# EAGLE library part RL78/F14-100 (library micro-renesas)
16-Bit Single-Chip Microcontroller Source: Data sheet

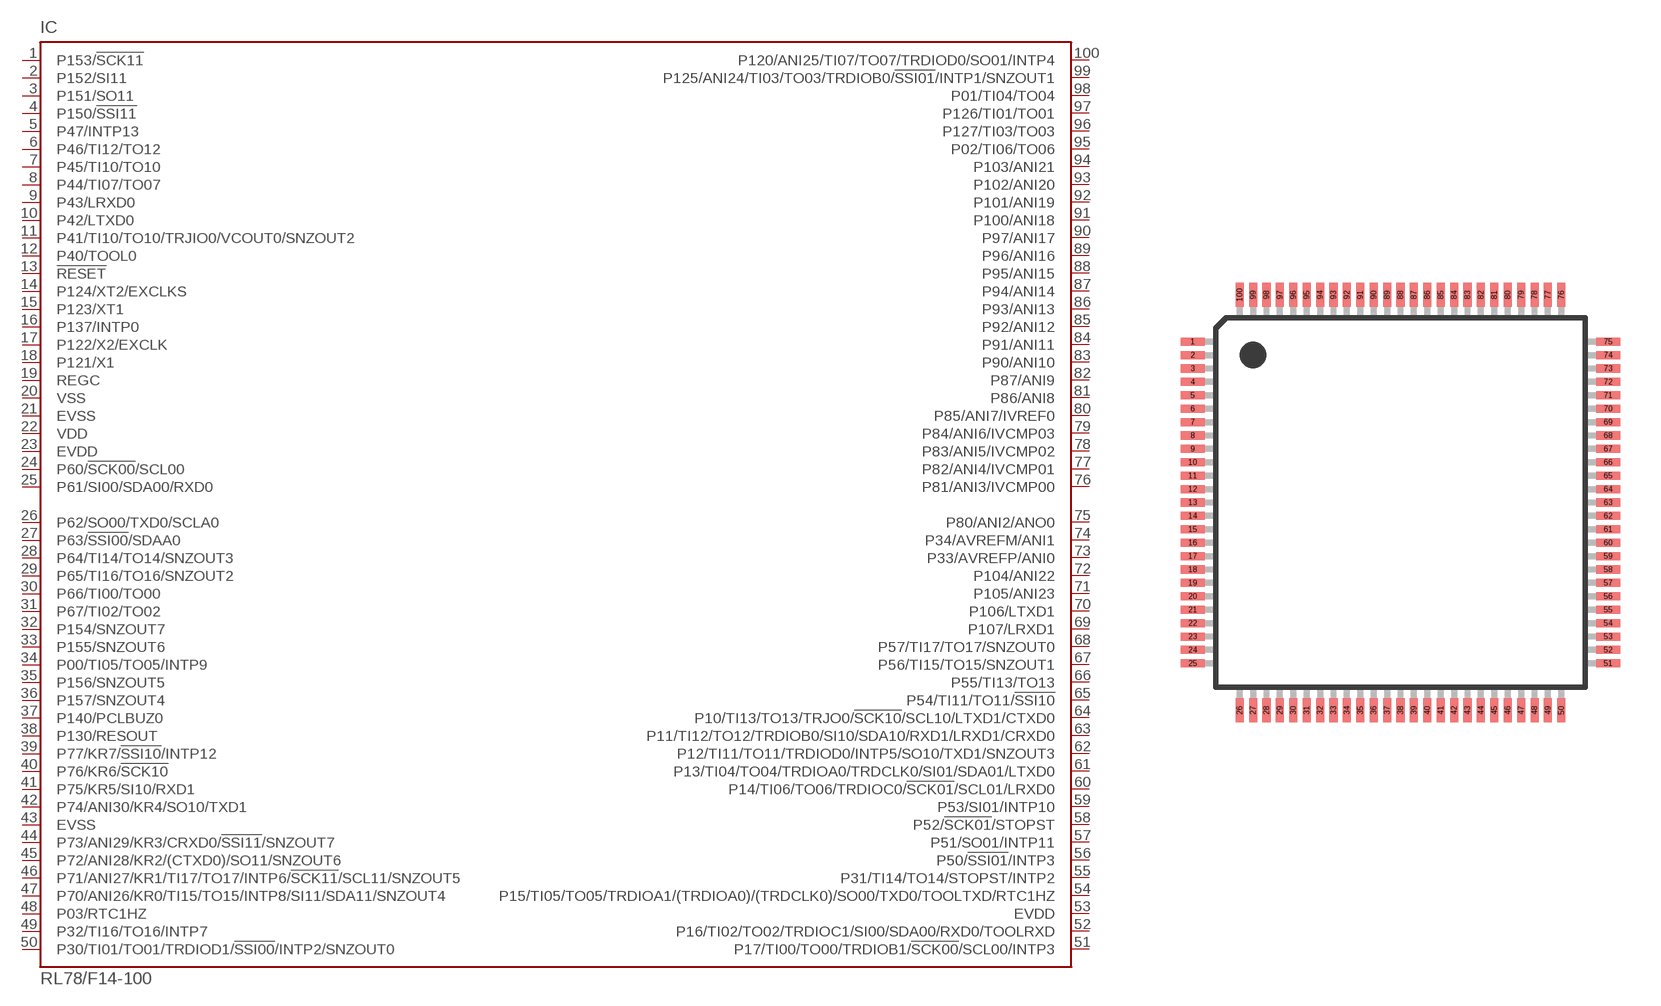
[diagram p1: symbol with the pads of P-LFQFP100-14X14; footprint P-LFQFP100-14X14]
Designator prefix IC

## RL78/F14-100  [P-LFQFP100-14X14]
1  P153/!SCK11
2  P152/SI11
3  P151/SO11
4  P150/!SSI11
5  P47/INTP13
6  P46/TI12/TO12
7  P45/TI10/TO10
8  P44/TI07/TO07
9  P43/LRXD0
10  P42/LTXD0
11  P41/TI10/TO10/TRJIO0/VCOUT0/SNZOUT2
12  P40/TOOL0
13  !RESET  in
14  P124/XT2/EXCLKS  in
15  P123/XT1  in
16  P137/INTP0  in
17  P122/X2/EXCLK  in
18  P121/X1  in
19  REGC  pas
20  VSS  pwr
21  EVSS  pwr
22  VDD  pwr
23  EVDD  pwr
24  P60/!SCK00!/SCL00
25  P61/SI00/SDA00/RXD0
26  P62/SO00/TXD0/SCLA0
27  P63/!SSI00!/SDAA0
28  P64/TI14/TO14/SNZOUT3
29  P65/TI16/TO16/SNZOUT2
30  P66/TI00/TO00
31  P67/TI02/TO02
32  P154/SNZOUT7
33  P155/SNZOUT6
34  P00/TI05/TO05/INTP9
35  P156/SNZOUT5
36  P157/SNZOUT4
37  P140/PCLBUZ0
38  P130/RESOUT
39  P77/KR7/!SSI10!/INTP12
40  P76/KR6/!SCK10
41  P75/KR5/SI10/RXD1
42  P74/ANI30/KR4/SO10/TXD1
43  EVSS  pwr
44  P73/ANI29/KR3/CRXD0/!SSI11!/SNZOUT7
45  P72/ANI28/KR2/(CTXD0)/SO11/SNZOUT6
46  P71/ANI27/KR1/TI17/TO17/INTP6/!SCK11!/SCL11/SNZOUT5
47  P70/ANI26/KR0/TI15/TO15/INTP8/SI11/SDA11/SNZOUT4
48  P03/RTC1HZ
49  P32/TI16/TO16/INTP7
50  P30/TI01/TO01/TRDIOD1/!SSI00!/INTP2/SNZOUT0
51  P17/TI00/TO00/TRDIOB1/!SCK00!/SCL00/INTP3
52  P16/TI02/TO02/TRDIOC1/SI00/SDA00/RXD0/TOOLRXD
53  EVDD  pwr
54  P15/TI05/TO05/TRDIOA1/(TRDIOA0)/(TRDCLK0)/SO00/TXD0/TOOLTXD/RTC1HZ
55  P31/TI14/TO14/STOPST/INTP2
56  P50/!SSI01!/INTP3
57  P51/SO01/INTP11
58  P52/!SCK01!/STOPST
59  P53/SI01/INTP10
60  P14/TI06/TO06/TRDIOC0/!SCK01!/SCL01/LRXD0
61  P13/TI04/TO04/TRDIOA0/TRDCLK0/SI01/SDA01/LTXD0
62  P12/TI11/TO11/TRDIOD0/INTP5/SO10/TXD1/SNZOUT3
63  P11/TI12/TO12/TRDIOB0/SI10/SDA10/RXD1/LRXD1/CRXD0
64  P10/TI13/TO13/TRJO0/!SCK10!/SCL10/LTXD1/CTXD0
65  P54/TI11/TO11/!SSI10
66  P55/TI13/TO13
67  P56/TI15/TO15/SNZOUT1
68  P57/TI17/TO17/SNZOUT0
69  P107/LRXD1
70  P106/LTXD1
71  P105/ANI23
72  P104/ANI22
73  P33/AVREFP/ANI0
74  P34/AVREFM/ANI1
75  P80/ANI2/ANO0
76  P81/ANI3/IVCMP00
77  P82/ANI4/IVCMP01
78  P83/ANI5/IVCMP02
79  P84/ANI6/IVCMP03
80  P85/ANI7/IVREF0
81  P86/ANI8
82  P87/ANI9
83  P90/ANI10
84  P91/ANI11
85  P92/ANI12
86  P93/ANI13
87  P94/ANI14
88  P95/ANI15
89  P96/ANI16
90  P97/ANI17
91  P100/ANI18
92  P101/ANI19
93  P102/ANI20
94  P103/ANI21
95  P02/TI06/TO06
96  P127/TI03/TO03
97  P126/TI01/TO01
98  P01/TI04/TO04
99  P125/ANI24/TI03/TO03/TRDIOB0/!SSI01!/INTP1/SNZOUT1
100  P120/ANI25/TI07/TO07/TRDIOD0/SO01/INTP4

## Footprint P-LFQFP100-14X14 (pad centres in mm)
P-LFQFP100-14X14 Auto generated by make-symbol-device-package-bsdl.ulp Rev. 43 JEITA Package code RENESAS code Previous code P-LFQFP100-14x14-0.50 PLQP0100KE-A P100GC-50-GBR-1
smd 0.9 x 0.3: 1 -7.75,6; 2 -7.75,5.5; 3 -7.75,5; 4 -7.75,4.5; 5 -7.75,4; 6 -7.75,3.5; 7 -7.75,3; 8 -7.75,2.5; 9 -7.75,2; 10 -7.75,1.5; 11 -7.75,1; 12 -7.75,0.5; 13 -7.75,0; 14 -7.75,-0.5; 15 -7.75,-1; 16 -7.75,-1.5; 17 -7.75,-2; 18 -7.75,-2.5; 19 -7.75,-3; 20 -7.75,-3.5; 21 -7.75,-4; 22 -7.75,-4.5; 23 -7.75,-5; 24 -7.75,-5.5; 25 -7.75,-6; 51 7.75,-6; 52 7.75,-5.5; 53 7.75,-5; 54 7.75,-4.5; 55 7.75,-4; 56 7.75,-3.5; 57 7.75,-3; 58 7.75,-2.5; 59 7.75,-2; 60 7.75,-1.5; 61 7.75,-1; 62 7.75,-0.5; 63 7.75,0; 64 7.75,0.5; 65 7.75,1; 66 7.75,1.5; 67 7.75,2; 68 7.75,2.5; 69 7.75,3; 70 7.75,3.5; 71 7.75,4; 72 7.75,4.5; 73 7.75,5; 74 7.75,5.5; 75 7.75,6
smd 0.3 x 0.9: 26 -6,-7.75; 27 -5.5,-7.75; 28 -5,-7.75; 29 -4.5,-7.75; 30 -4,-7.75; 31 -3.5,-7.75; 32 -3,-7.75; 33 -2.5,-7.75; 34 -2,-7.75; 35 -1.5,-7.75; 36 -1,-7.75; 37 -0.5,-7.75; 38 0,-7.75; 39 0.5,-7.75; 40 1,-7.75; 41 1.5,-7.75; 42 2,-7.75; 43 2.5,-7.75; 44 3,-7.75; 45 3.5,-7.75; 46 4,-7.75; 47 4.5,-7.75; 48 5,-7.75; 49 5.5,-7.75; 50 6,-7.75; 76 6,7.75; 77 5.5,7.75; 78 5,7.75; 79 4.5,7.75; 80 4,7.75; 81 3.5,7.75; 82 3,7.75; 83 2.5,7.75; 84 2,7.75; 85 1.5,7.75; 86 1,7.75; 87 0.5,7.75; 88 0,7.75; 89 -0.5,7.75; 90 -1,7.75; 91 -1.5,7.75; 92 -2,7.75; 93 -2.5,7.75; 94 -3,7.75; 95 -3.5,7.75; 96 -4,7.75; 97 -4.5,7.75; 98 -5,7.75; 99 -5.5,7.75; 100 -6,7.75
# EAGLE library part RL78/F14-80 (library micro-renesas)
16-Bit Single-Chip Microcontroller Source: Data sheet

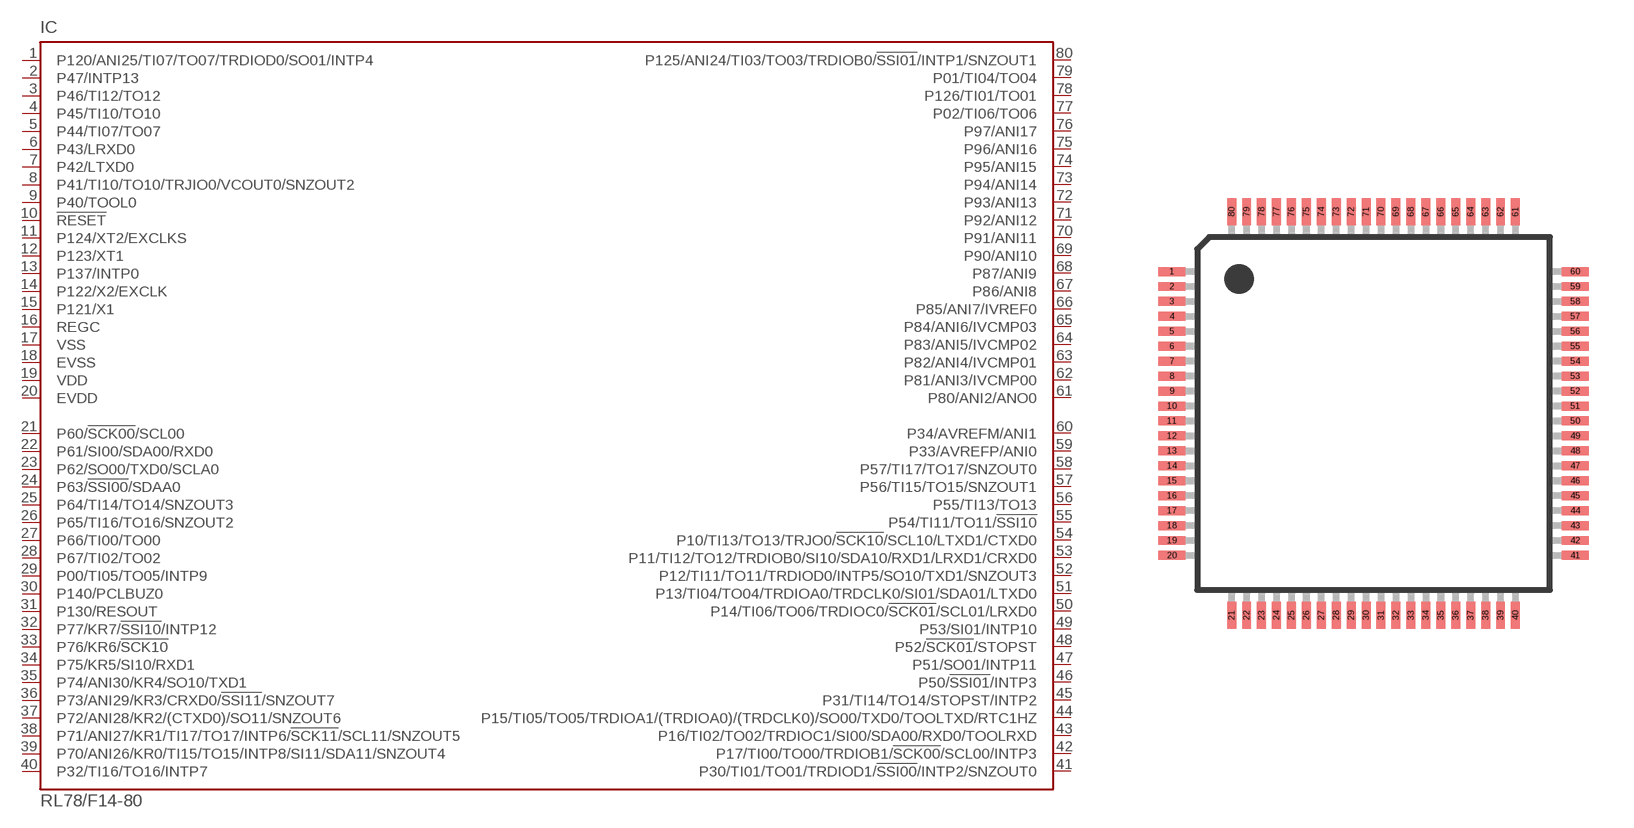
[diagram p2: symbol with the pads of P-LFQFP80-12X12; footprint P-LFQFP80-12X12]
Designator prefix IC

## RL78/F14-80  [P-LFQFP80-12X12]
1  P120/ANI25/TI07/TO07/TRDIOD0/SO01/INTP4
2  P47/INTP13
3  P46/TI12/TO12
4  P45/TI10/TO10
5  P44/TI07/TO07
6  P43/LRXD0
7  P42/LTXD0
8  P41/TI10/TO10/TRJIO0/VCOUT0/SNZOUT2
9  P40/TOOL0
10  !RESET  in
11  P124/XT2/EXCLKS  in
12  P123/XT1  in
13  P137/INTP0  in
14  P122/X2/EXCLK  in
15  P121/X1  in
16  REGC  pas
17  VSS  pwr
18  EVSS  pwr
19  VDD  pwr
20  EVDD  pwr
21  P60/!SCK00!/SCL00
22  P61/SI00/SDA00/RXD0
23  P62/SO00/TXD0/SCLA0
24  P63/!SSI00!/SDAA0
25  P64/TI14/TO14/SNZOUT3
26  P65/TI16/TO16/SNZOUT2
27  P66/TI00/TO00
28  P67/TI02/TO02
29  P00/TI05/TO05/INTP9
30  P140/PCLBUZ0
31  P130/RESOUT
32  P77/KR7/!SSI10!/INTP12
33  P76/KR6/!SCK10
34  P75/KR5/SI10/RXD1
35  P74/ANI30/KR4/SO10/TXD1
36  P73/ANI29/KR3/CRXD0/!SSI11!/SNZOUT7
37  P72/ANI28/KR2/(CTXD0)/SO11/SNZOUT6
38  P71/ANI27/KR1/TI17/TO17/INTP6/!SCK11!/SCL11/SNZOUT5
39  P70/ANI26/KR0/TI15/TO15/INTP8/SI11/SDA11/SNZOUT4
40  P32/TI16/TO16/INTP7
41  P30/TI01/TO01/TRDIOD1/!SSI00!/INTP2/SNZOUT0
42  P17/TI00/TO00/TRDIOB1/!SCK00!/SCL00/INTP3
43  P16/TI02/TO02/TRDIOC1/SI00/SDA00/RXD0/TOOLRXD
44  P15/TI05/TO05/TRDIOA1/(TRDIOA0)/(TRDCLK0)/SO00/TXD0/TOOLTXD/RTC1HZ
45  P31/TI14/TO14/STOPST/INTP2
46  P50/!SSI01!/INTP3
47  P51/SO01/INTP11
48  P52/!SCK01!/STOPST
49  P53/SI01/INTP10
50  P14/TI06/TO06/TRDIOC0/!SCK01!/SCL01/LRXD0
51  P13/TI04/TO04/TRDIOA0/TRDCLK0/SI01/SDA01/LTXD0
52  P12/TI11/TO11/TRDIOD0/INTP5/SO10/TXD1/SNZOUT3
53  P11/TI12/TO12/TRDIOB0/SI10/SDA10/RXD1/LRXD1/CRXD0
54  P10/TI13/TO13/TRJO0/!SCK10!/SCL10/LTXD1/CTXD0
55  P54/TI11/TO11/!SSI10
56  P55/TI13/TO13
57  P56/TI15/TO15/SNZOUT1
58  P57/TI17/TO17/SNZOUT0
59  P33/AVREFP/ANI0
60  P34/AVREFM/ANI1
61  P80/ANI2/ANO0
62  P81/ANI3/IVCMP00
63  P82/ANI4/IVCMP01
64  P83/ANI5/IVCMP02
65  P84/ANI6/IVCMP03
66  P85/ANI7/IVREF0
67  P86/ANI8
68  P87/ANI9
69  P90/ANI10
70  P91/ANI11
71  P92/ANI12
72  P93/ANI13
73  P94/ANI14
74  P95/ANI15
75  P96/ANI16
76  P97/ANI17
77  P02/TI06/TO06
78  P126/TI01/TO01
79  P01/TI04/TO04
80  P125/ANI24/TI03/TO03/TRDIOB0/!SSI01!/INTP1/SNZOUT1

## Footprint P-LFQFP80-12X12 (pad centres in mm)
P-LFQFP80-12X12 Auto generated by make-symbol-device-package-bsdl.ulp Rev. 43 JEITA Package code RENESAS code Previous code P-LFQFP80-12x12-0.50 PLQP0080KE-A P80GK-50-8EU-2
smd 0.9 x 0.3: 1 -6.75,4.75; 2 -6.75,4.25; 3 -6.75,3.75; 4 -6.75,3.25; 5 -6.75,2.75; 6 -6.75,2.25; 7 -6.75,1.75; 8 -6.75,1.25; 9 -6.75,0.75; 10 -6.75,0.25; 11 -6.75,-0.25; 12 -6.75,-0.75; 13 -6.75,-1.25; 14 -6.75,-1.75; 15 -6.75,-2.25; 16 -6.75,-2.75; 17 -6.75,-3.25; 18 -6.75,-3.75; 19 -6.75,-4.25; 20 -6.75,-4.75; 41 6.75,-4.75; 42 6.75,-4.25; 43 6.75,-3.75; 44 6.75,-3.25; 45 6.75,-2.75; 46 6.75,-2.25; 47 6.75,-1.75; 48 6.75,-1.25; 49 6.75,-0.75; 50 6.75,-0.25; 51 6.75,0.25; 52 6.75,0.75; 53 6.75,1.25; 54 6.75,1.75; 55 6.75,2.25; 56 6.75,2.75; 57 6.75,3.25; 58 6.75,3.75; 59 6.75,4.25; 60 6.75,4.75
smd 0.3 x 0.9: 21 -4.75,-6.75; 22 -4.25,-6.75; 23 -3.75,-6.75; 24 -3.25,-6.75; 25 -2.75,-6.75; 26 -2.25,-6.75; 27 -1.75,-6.75; 28 -1.25,-6.75; 29 -0.75,-6.75; 30 -0.25,-6.75; 31 0.25,-6.75; 32 0.75,-6.75; 33 1.25,-6.75; 34 1.75,-6.75; 35 2.25,-6.75; 36 2.75,-6.75; 37 3.25,-6.75; 38 3.75,-6.75; 39 4.25,-6.75; 40 4.75,-6.75; 61 4.75,6.75; 62 4.25,6.75; 63 3.75,6.75; 64 3.25,6.75; 65 2.75,6.75; 66 2.25,6.75; 67 1.75,6.75; 68 1.25,6.75; 69 0.75,6.75; 70 0.25,6.75; 71 -0.25,6.75; 72 -0.75,6.75; 73 -1.25,6.75; 74 -1.75,6.75; 75 -2.25,6.75; 76 -2.75,6.75; 77 -3.25,6.75; 78 -3.75,6.75; 79 -4.25,6.75; 80 -4.75,6.75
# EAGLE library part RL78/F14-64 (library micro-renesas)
16-Bit Single-Chip Microcontroller Source: Data sheet

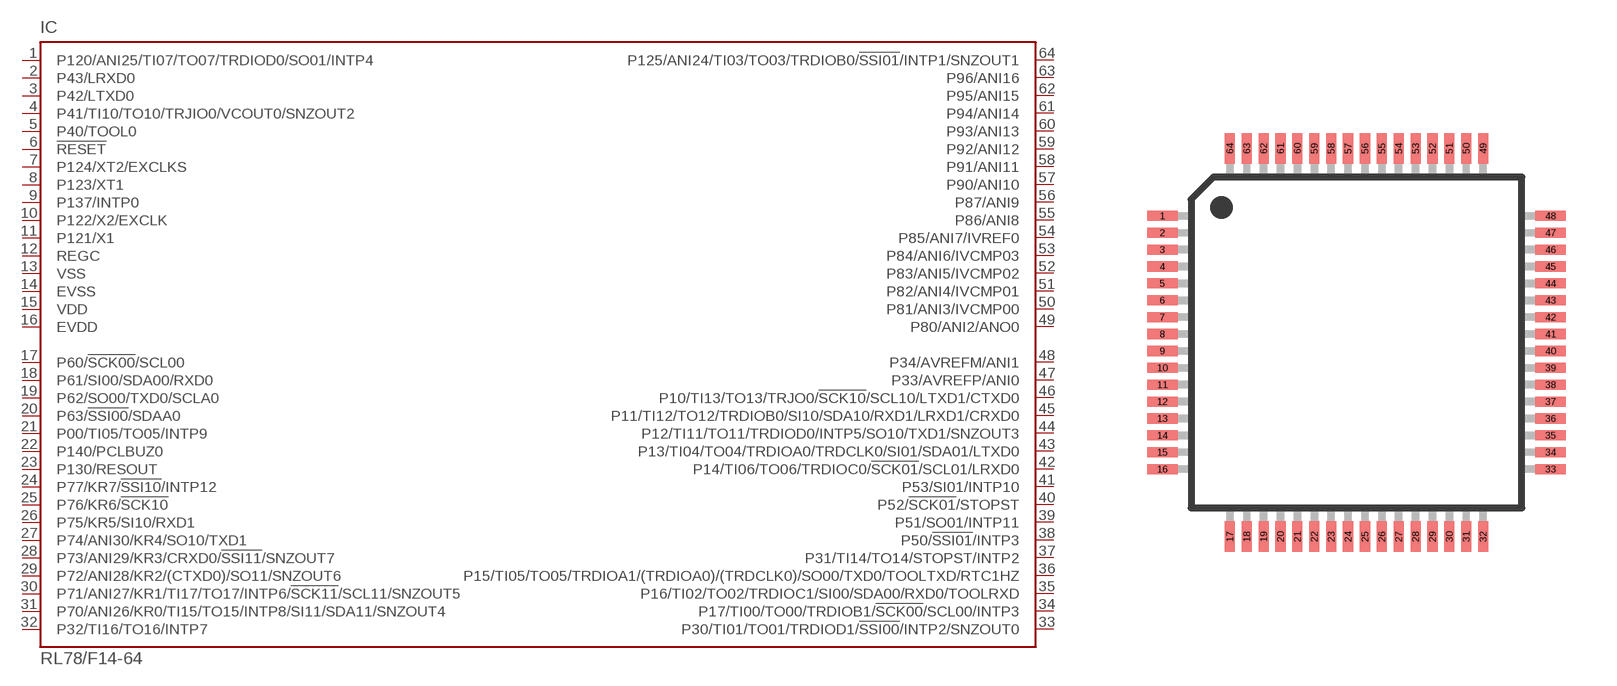
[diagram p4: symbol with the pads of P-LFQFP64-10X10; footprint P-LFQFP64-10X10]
Designator prefix IC

## RL78/F14-64  [P-LFQFP64-10X10]
1  P120/ANI25/TI07/TO07/TRDIOD0/SO01/INTP4
2  P43/LRXD0
3  P42/LTXD0
4  P41/TI10/TO10/TRJIO0/VCOUT0/SNZOUT2
5  P40/TOOL0
6  !RESET  in
7  P124/XT2/EXCLKS  in
8  P123/XT1  in
9  P137/INTP0  in
10  P122/X2/EXCLK  in
11  P121/X1  in
12  REGC  pas
13  VSS  pwr
14  EVSS  pwr
15  VDD  pwr
16  EVDD  pwr
17  P60/!SCK00!/SCL00
18  P61/SI00/SDA00/RXD0
19  P62/SO00/TXD0/SCLA0
20  P63/!SSI00!/SDAA0
21  P00/TI05/TO05/INTP9
22  P140/PCLBUZ0
23  P130/RESOUT
24  P77/KR7/!SSI10!/INTP12
25  P76/KR6/!SCK10
26  P75/KR5/SI10/RXD1
27  P74/ANI30/KR4/SO10/TXD1
28  P73/ANI29/KR3/CRXD0/!SSI11!/SNZOUT7
29  P72/ANI28/KR2/(CTXD0)/SO11/SNZOUT6
30  P71/ANI27/KR1/TI17/TO17/INTP6/!SCK11!/SCL11/SNZOUT5
31  P70/ANI26/KR0/TI15/TO15/INTP8/SI11/SDA11/SNZOUT4
32  P32/TI16/TO16/INTP7
33  P30/TI01/TO01/TRDIOD1/!SSI00!/INTP2/SNZOUT0
34  P17/TI00/TO00/TRDIOB1/!SCK00!/SCL00/INTP3
35  P16/TI02/TO02/TRDIOC1/SI00/SDA00/RXD0/TOOLRXD
36  P15/TI05/TO05/TRDIOA1/(TRDIOA0)/(TRDCLK0)/SO00/TXD0/TOOLTXD/RTC1HZ
37  P31/TI14/TO14/STOPST/INTP2
38  P50/!SSI01!/INTP3
39  P51/SO01/INTP11
40  P52/!SCK01!/STOPST
41  P53/SI01/INTP10
42  P14/TI06/TO06/TRDIOC0/!SCK01!/SCL01/LRXD0
43  P13/TI04/TO04/TRDIOA0/TRDCLK0/SI01/SDA01/LTXD0
44  P12/TI11/TO11/TRDIOD0/INTP5/SO10/TXD1/SNZOUT3
45  P11/TI12/TO12/TRDIOB0/SI10/SDA10/RXD1/LRXD1/CRXD0
46  P10/TI13/TO13/TRJO0/!SCK10!/SCL10/LTXD1/CTXD0
47  P33/AVREFP/ANI0
48  P34/AVREFM/ANI1
49  P80/ANI2/ANO0
50  P81/ANI3/IVCMP00
51  P82/ANI4/IVCMP01
52  P83/ANI5/IVCMP02
53  P84/ANI6/IVCMP03
54  P85/ANI7/IVREF0
55  P86/ANI8
56  P87/ANI9
57  P90/ANI10
58  P91/ANI11
59  P92/ANI12
60  P93/ANI13
61  P94/ANI14
62  P95/ANI15
63  P96/ANI16
64  P125/ANI24/TI03/TO03/TRDIOB0/!SSI01!/INTP1/SNZOUT1

## Footprint P-LFQFP64-10X10 (pad centres in mm)
P-LFQFP64-10X10 Auto generated by make-symbol-device-package-bsdl.ulp Rev. 43
smd 0.9 x 0.3: 1 -5.75,3.75; 2 -5.75,3.25; 3 -5.75,2.75; 4 -5.75,2.25; 5 -5.75,1.75; 6 -5.75,1.25; 7 -5.75,0.75; 8 -5.75,0.25; 9 -5.75,-0.25; 10 -5.75,-0.75; 11 -5.75,-1.25; 12 -5.75,-1.75; 13 -5.75,-2.25; 14 -5.75,-2.75; 15 -5.75,-3.25; 16 -5.75,-3.75; 33 5.75,-3.75; 34 5.75,-3.25; 35 5.75,-2.75; 36 5.75,-2.25; 37 5.75,-1.75; 38 5.75,-1.25; 39 5.75,-0.75; 40 5.75,-0.25; 41 5.75,0.25; 42 5.75,0.75; 43 5.75,1.25; 44 5.75,1.75; 45 5.75,2.25; 46 5.75,2.75; 47 5.75,3.25; 48 5.75,3.75
smd 0.3 x 0.9: 17 -3.75,-5.75; 18 -3.25,-5.75; 19 -2.75,-5.75; 20 -2.25,-5.75; 21 -1.75,-5.75; 22 -1.25,-5.75; 23 -0.75,-5.75; 24 -0.25,-5.75; 25 0.25,-5.75; 26 0.75,-5.75; 27 1.25,-5.75; 28 1.75,-5.75; 29 2.25,-5.75; 30 2.75,-5.75; 31 3.25,-5.75; 32 3.75,-5.75; 49 3.75,5.75; 50 3.25,5.75; 51 2.75,5.75; 52 2.25,5.75; 53 1.75,5.75; 54 1.25,5.75; 55 0.75,5.75; 56 0.25,5.75; 57 -0.25,5.75; 58 -0.75,5.75; 59 -1.25,5.75; 60 -1.75,5.75; 61 -2.25,5.75; 62 -2.75,5.75; 63 -3.25,5.75; 64 -3.75,5.75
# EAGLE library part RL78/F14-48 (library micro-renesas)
16-Bit Single-Chip Microcontroller Source: Data sheet

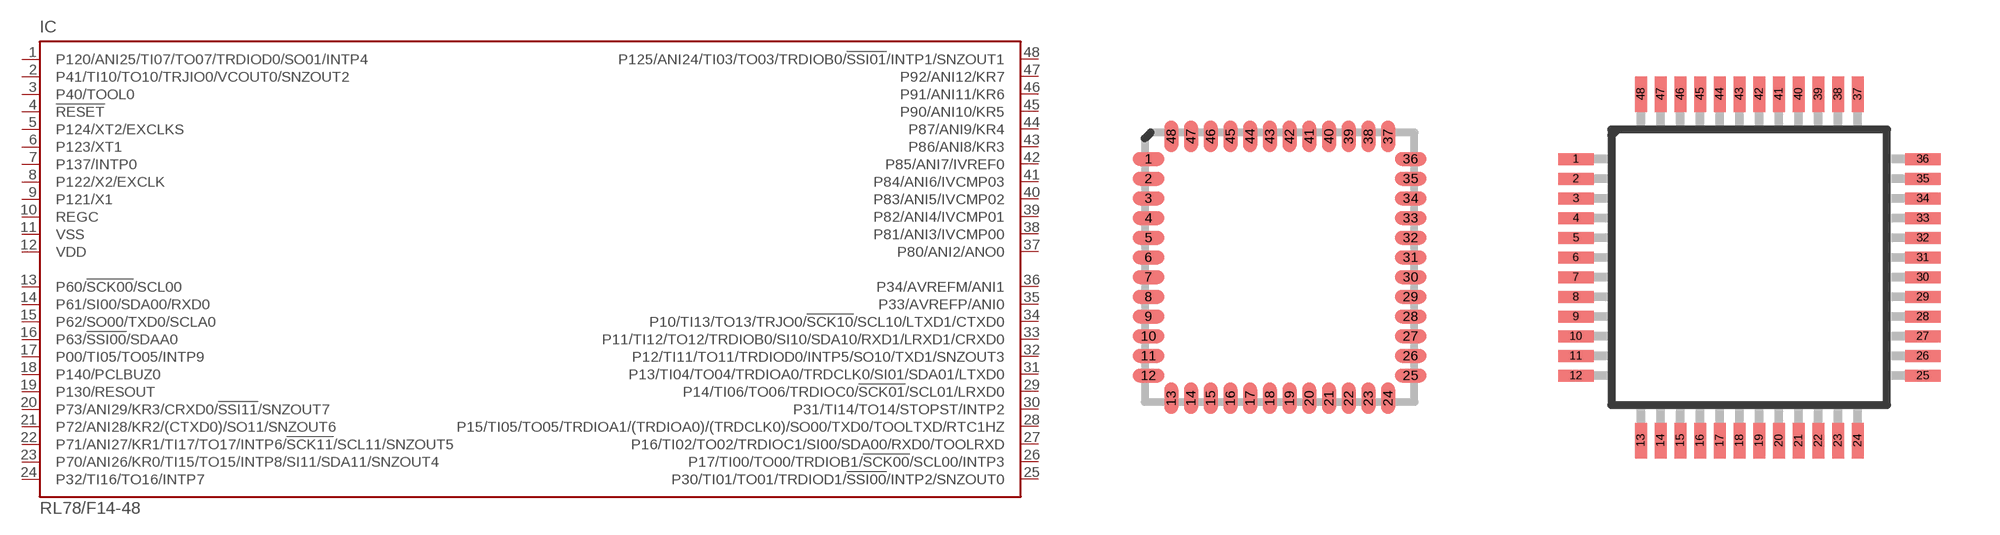
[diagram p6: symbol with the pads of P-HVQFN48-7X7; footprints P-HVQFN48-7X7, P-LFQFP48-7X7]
Designator prefix IC

## RL78/F14-48VQFN  [P-HVQFN48-7X7]
1  P120/ANI25/TI07/TO07/TRDIOD0/SO01/INTP4
2  P41/TI10/TO10/TRJIO0/VCOUT0/SNZOUT2
3  P40/TOOL0
4  !RESET  in
5  P124/XT2/EXCLKS  in
6  P123/XT1  in
7  P137/INTP0  in
8  P122/X2/EXCLK  in
9  P121/X1  in
10  REGC  pas
11  VSS  pwr
12  VDD  pwr
13  P60/!SCK00!/SCL00
14  P61/SI00/SDA00/RXD0
15  P62/SO00/TXD0/SCLA0
16  P63/!SSI00!/SDAA0
17  P00/TI05/TO05/INTP9
18  P140/PCLBUZ0
19  P130/RESOUT
20  P73/ANI29/KR3/CRXD0/!SSI11!/SNZOUT7
21  P72/ANI28/KR2/(CTXD0)/SO11/SNZOUT6
22  P71/ANI27/KR1/TI17/TO17/INTP6/!SCK11!/SCL11/SNZOUT5
23  P70/ANI26/KR0/TI15/TO15/INTP8/SI11/SDA11/SNZOUT4
24  P32/TI16/TO16/INTP7
25  P30/TI01/TO01/TRDIOD1/!SSI00!/INTP2/SNZOUT0
26  P17/TI00/TO00/TRDIOB1/!SCK00!/SCL00/INTP3
27  P16/TI02/TO02/TRDIOC1/SI00/SDA00/RXD0/TOOLRXD
28  P15/TI05/TO05/TRDIOA1/(TRDIOA0)/(TRDCLK0)/SO00/TXD0/TOOLTXD/RTC1HZ
29  P14/TI06/TO06/TRDIOC0/!SCK01!/SCL01/LRXD0
30  P31/TI14/TO14/STOPST/INTP2
31  P13/TI04/TO04/TRDIOA0/TRDCLK0/SI01/SDA01/LTXD0
32  P12/TI11/TO11/TRDIOD0/INTP5/SO10/TXD1/SNZOUT3
33  P11/TI12/TO12/TRDIOB0/SI10/SDA10/RXD1/LRXD1/CRXD0
34  P10/TI13/TO13/TRJO0/!SCK10!/SCL10/LTXD1/CTXD0
35  P33/AVREFP/ANI0
36  P34/AVREFM/ANI1
37  P80/ANI2/ANO0
38  P81/ANI3/IVCMP00
39  P82/ANI4/IVCMP01
40  P83/ANI5/IVCMP02
41  P84/ANI6/IVCMP03
42  P85/ANI7/IVREF0
43  P86/ANI8/KR3
44  P87/ANI9/KR4
45  P90/ANI10/KR5
46  P91/ANI11/KR6
47  P92/ANI12/KR7
48  P125/ANI24/TI03/TO03/TRDIOB0/!SSI01!/INTP1/SNZOUT1

## RL78/F14-48LQFP  [P-LFQFP48-7X7]
Pads as for P-HVQFN48-7X7

## Footprint P-HVQFN48-7X7 (pad centres in mm)
P-HVQFN48-7X7 Auto generated by make-symbol-device-package-bsdl.ulp Rev. 43 JEITA Package code RENESAS code Previous code P-HVQFN48-7x7-0.50 PVQN0048KG-A P48K9-50A-BAJ
smd 0.8 x 0.35: 1 -3.325,2.75; 2 -3.325,2.25; 3 -3.325,1.75; 4 -3.325,1.25; 5 -3.325,0.75; 6 -3.325,0.25; 7 -3.325,-0.25; 8 -3.325,-0.75; 9 -3.325,-1.25; 10 -3.325,-1.75; 11 -3.325,-2.25; 12 -3.325,-2.75; 25 3.325,-2.75; 26 3.325,-2.25; 27 3.325,-1.75; 28 3.325,-1.25; 29 3.325,-0.75; 30 3.325,-0.25; 31 3.325,0.25; 32 3.325,0.75; 33 3.325,1.25; 34 3.325,1.75; 35 3.325,2.25; 36 3.325,2.75
smd 0.35 x 0.8: 13 -2.75,-3.325; 14 -2.25,-3.325; 15 -1.75,-3.325; 16 -1.25,-3.325; 17 -0.75,-3.325; 18 -0.25,-3.325; 19 0.25,-3.325; 20 0.75,-3.325; 21 1.25,-3.325; 22 1.75,-3.325; 23 2.25,-3.325; 24 2.75,-3.325; 37 2.75,3.325; 38 2.25,3.325; 39 1.75,3.325; 40 1.25,3.325; 41 0.75,3.325; 42 0.25,3.325; 43 -0.25,3.325; 44 -0.75,3.325; 45 -1.25,3.325; 46 -1.75,3.325; 47 -2.25,3.325; 48 -2.75,3.325

## Footprint P-LFQFP48-7X7 (pad centres in mm)
P-LFQFP48-7X7 Auto generated by make-symbol-device-package-bsdl.ulp Rev. 43 JEITA Package code RENESAS code Previous code P-LFQFP48-7x7-0.50 PLQP0048KF-A P48GA-50-8EU-1
smd 0.9 x 0.3: 1 -4.4,2.75; 2 -4.4,2.25; 3 -4.4,1.75; 4 -4.4,1.25; 5 -4.4,0.75; 6 -4.4,0.25; 7 -4.4,-0.25; 8 -4.4,-0.75; 9 -4.4,-1.25; 10 -4.4,-1.75; 11 -4.4,-2.25; 12 -4.4,-2.75; 25 4.4,-2.75; 26 4.4,-2.25; 27 4.4,-1.75; 28 4.4,-1.25; 29 4.4,-0.75; 30 4.4,-0.25; 31 4.4,0.25; 32 4.4,0.75; 33 4.4,1.25; 34 4.4,1.75; 35 4.4,2.25; 36 4.4,2.75
smd 0.3 x 0.9: 13 -2.75,-4.4; 14 -2.25,-4.4; 15 -1.75,-4.4; 16 -1.25,-4.4; 17 -0.75,-4.4; 18 -0.25,-4.4; 19 0.25,-4.4; 20 0.75,-4.4; 21 1.25,-4.4; 22 1.75,-4.4; 23 2.25,-4.4; 24 2.75,-4.4; 37 2.75,4.4; 38 2.25,4.4; 39 1.75,4.4; 40 1.25,4.4; 41 0.75,4.4; 42 0.25,4.4; 43 -0.25,4.4; 44 -0.75,4.4; 45 -1.25,4.4; 46 -1.75,4.4; 47 -2.25,4.4; 48 -2.75,4.4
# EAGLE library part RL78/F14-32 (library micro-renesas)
16-Bit Single-Chip Microcontroller Source: Data sheet

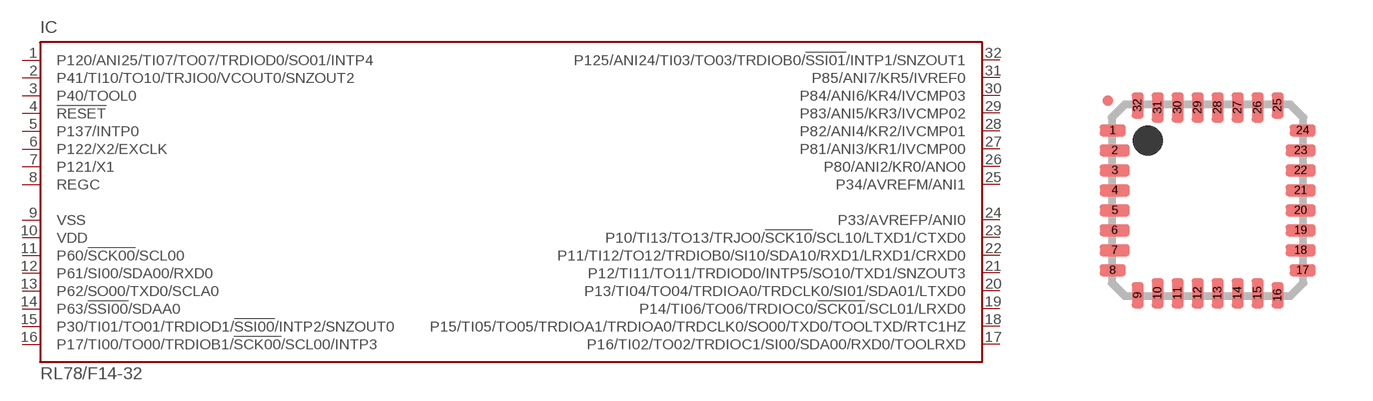
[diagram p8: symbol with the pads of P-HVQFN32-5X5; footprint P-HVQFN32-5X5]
Designator prefix IC

## RL78/F14-32  [P-HVQFN32-5X5]
1  P120/ANI25/TI07/TO07/TRDIOD0/SO01/INTP4
2  P41/TI10/TO10/TRJIO0/VCOUT0/SNZOUT2
3  P40/TOOL0
4  !RESET  in
5  P137/INTP0  in
6  P122/X2/EXCLK  in
7  P121/X1  in
8  REGC  pas
9  VSS  pwr
10  VDD  pwr
11  P60/!SCK00!/SCL00
12  P61/SI00/SDA00/RXD0
13  P62/SO00/TXD0/SCLA0
14  P63/!SSI00!/SDAA0
15  P30/TI01/TO01/TRDIOD1/!SSI00!/INTP2/SNZOUT0
16  P17/TI00/TO00/TRDIOB1/!SCK00!/SCL00/INTP3
17  P16/TI02/TO02/TRDIOC1/SI00/SDA00/RXD0/TOOLRXD
18  P15/TI05/TO05/TRDIOA1/TRDIOA0/TRDCLK0/SO00/TXD0/TOOLTXD/RTC1HZ
19  P14/TI06/TO06/TRDIOC0/!SCK01!/SCL01/LRXD0
20  P13/TI04/TO04/TRDIOA0/TRDCLK0/SI01/SDA01/LTXD0
21  P12/TI11/TO11/TRDIOD0/INTP5/SO10/TXD1/SNZOUT3
22  P11/TI12/TO12/TRDIOB0/SI10/SDA10/RXD1/LRXD1/CRXD0
23  P10/TI13/TO13/TRJO0/!SCK10!/SCL10/LTXD1/CTXD0
24  P33/AVREFP/ANI0
25  P34/AVREFM/ANI1
26  P80/ANI2/KR0/ANO0
27  P81/ANI3/KR1/IVCMP00
28  P82/ANI4/KR2/IVCMP01
29  P83/ANI5/KR3/IVCMP02
30  P84/ANI6/KR4/IVCMP03
31  P85/ANI7/KR5/IVREF0
32  P125/ANI24/TI03/TO03/TRDIOB0/!SSI01!/INTP1/SNZOUT1

## Footprint P-HVQFN32-5X5 (pad centres in mm)
P-HVQFN32-5X5 Auto generated by make-symbol-device-package-bsdl.ulp Rev. 43 Source: Data sheet JEITA Package code RENESAS code Previous code P-HVQFN32-5x5-0.50 PVQN0032KD-A P32K9-50A-BAH
smd 0.65 x 0.3: 1 -2.375,1.75; 8 -2.375,-1.75; 17 2.375,-1.75; 24 2.375,1.75
smd 0.75 x 0.3: 2 -2.325,1.25; 3 -2.325,0.75; 4 -2.325,0.25; 5 -2.325,-0.25; 6 -2.325,-0.75; 7 -2.325,-1.25; 18 2.325,-1.25; 19 2.325,-0.75; 20 2.325,-0.25; 21 2.325,0.25; 22 2.325,0.75; 23 2.325,1.25
smd 0.3 x 0.65: 9 -1.75,-2.375; 16 1.75,-2.375; 25 1.75,2.375; 32 -1.75,2.375
smd 0.3 x 0.75: 10 -1.25,-2.325; 11 -0.75,-2.325; 12 -0.25,-2.325; 13 0.25,-2.325; 14 0.75,-2.325; 15 1.25,-2.325; 26 1.25,2.325; 27 0.75,2.325; 28 0.25,2.325; 29 -0.25,2.325; 30 -0.75,2.325; 31 -1.25,2.325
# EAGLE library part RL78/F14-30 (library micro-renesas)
16-Bit Single-Chip Microcontroller Source: Data sheet

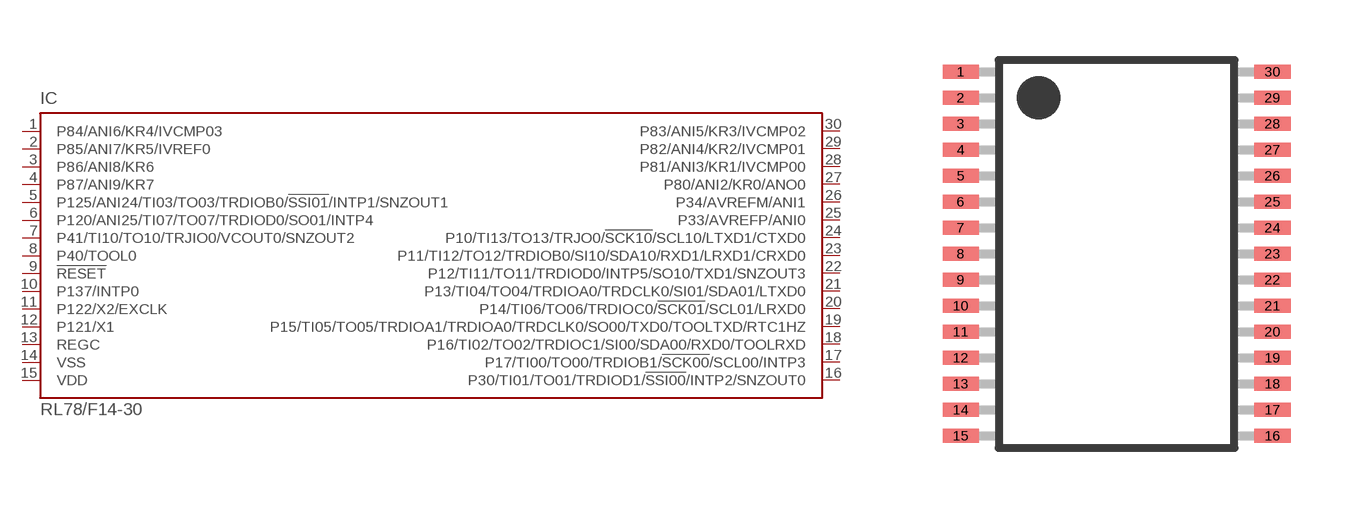
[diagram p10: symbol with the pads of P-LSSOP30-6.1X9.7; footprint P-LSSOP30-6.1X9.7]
Designator prefix IC

## RL78/F14-30  [P-LSSOP30-6.1X9.7]
1  P84/ANI6/KR4/IVCMP03
2  P85/ANI7/KR5/IVREF0
3  P86/ANI8/KR6
4  P87/ANI9/KR7
5  P125/ANI24/TI03/TO03/TRDIOB0/!SSI01!/INTP1/SNZOUT1
6  P120/ANI25/TI07/TO07/TRDIOD0/SO01/INTP4
7  P41/TI10/TO10/TRJIO0/VCOUT0/SNZOUT2
8  P40/TOOL0
9  !RESET  in
10  P137/INTP0  in
11  P122/X2/EXCLK  in
12  P121/X1  in
13  REGC  pas
14  VSS  pwr
15  VDD  pwr
16  P30/TI01/TO01/TRDIOD1/!SSI00!/INTP2/SNZOUT0
17  P17/TI00/TO00/TRDIOB1/!SCK00!/SCL00/INTP3
18  P16/TI02/TO02/TRDIOC1/SI00/SDA00/RXD0/TOOLRXD
19  P15/TI05/TO05/TRDIOA1/TRDIOA0/TRDCLK0/SO00/TXD0/TOOLTXD/RTC1HZ
20  P14/TI06/TO06/TRDIOC0/!SCK01!/SCL01/LRXD0
21  P13/TI04/TO04/TRDIOA0/TRDCLK0/SI01/SDA01/LTXD0
22  P12/TI11/TO11/TRDIOD0/INTP5/SO10/TXD1/SNZOUT3
23  P11/TI12/TO12/TRDIOB0/SI10/SDA10/RXD1/LRXD1/CRXD0
24  P10/TI13/TO13/TRJO0/!SCK10!/SCL10/LTXD1/CTXD0
25  P33/AVREFP/ANI0
26  P34/AVREFM/ANI1
27  P80/ANI2/KR0/ANO0
28  P81/ANI3/KR1/IVCMP00
29  P82/ANI4/KR2/IVCMP01
30  P83/ANI5/KR3/IVCMP02

## Footprint P-LSSOP30-6.1X9.7 (pad centres in mm)
P-LSSOP30-6.1X9.7 Auto generated by make-symbol-device-package-bsdl.ulp Rev. 43 JEITA Package code RENESAS code Previous code P-LSSOP30-6.1x9.7-0.65 PLSP0030JB-A P30MC-65-CAB-2
smd 0.9 x 0.35: 1 -3.9,4.55; 2 -3.9,3.9; 3 -3.9,3.25; 4 -3.9,2.6; 5 -3.9,1.95; 6 -3.9,1.3; 7 -3.9,0.65; 8 -3.9,0; 9 -3.9,-0.65; 10 -3.9,-1.3; 11 -3.9,-1.95; 12 -3.9,-2.6; 13 -3.9,-3.25; 14 -3.9,-3.9; 15 -3.9,-4.55; 16 3.9,-4.55; 17 3.9,-3.9; 18 3.9,-3.25; 19 3.9,-2.6; 20 3.9,-1.95; 21 3.9,-1.3; 22 3.9,-0.65; 23 3.9,0; 24 3.9,0.65; 25 3.9,1.3; 26 3.9,1.95; 27 3.9,2.6; 28 3.9,3.25; 29 3.9,3.9; 30 3.9,4.55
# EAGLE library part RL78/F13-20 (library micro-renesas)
16-Bit Single-Chip Microcontroller Source: Data sheet

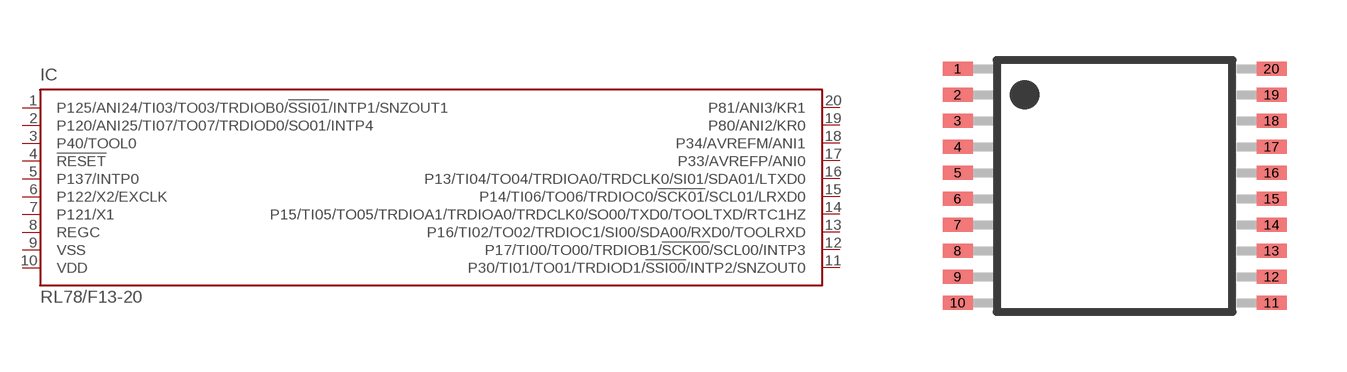
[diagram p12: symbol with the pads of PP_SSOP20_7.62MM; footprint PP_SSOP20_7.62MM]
Designator prefix IC

## RL78/F13-20  [PP_SSOP20_7.62MM]
1  P125/ANI24/TI03/TO03/TRDIOB0/!SSI01!/INTP1/SNZOUT1
2  P120/ANI25/TI07/TO07/TRDIOD0/SO01/INTP4
3  P40/TOOL0
4  !RESET  in
5  P137/INTP0  in
6  P122/X2/EXCLK  in
7  P121/X1  in
8  REGC  pas
9  VSS  pwr
10  VDD  pwr
11  P30/TI01/TO01/TRDIOD1/!SSI00!/INTP2/SNZOUT0
12  P17/TI00/TO00/TRDIOB1/!SCK00!/SCL00/INTP3
13  P16/TI02/TO02/TRDIOC1/SI00/SDA00/RXD0/TOOLRXD
14  P15/TI05/TO05/TRDIOA1/TRDIOA0/TRDCLK0/SO00/TXD0/TOOLTXD/RTC1HZ
15  P14/TI06/TO06/TRDIOC0/!SCK01!/SCL01/LRXD0
16  P13/TI04/TO04/TRDIOA0/TRDCLK0/SI01/SDA01/LTXD0
17  P33/AVREFP/ANI0
18  P34/AVREFM/ANI1
19  P80/ANI2/KR0
20  P81/ANI3/KR1

## Footprint PP_SSOP20_7.62MM (pad centres in mm)
PP_SSOP20_7.62MM Auto generated by make-symbol-device-package-bsdl.ulp Rev. 43
smd 0.75 x 0.35: 1 -3.925,2.925; 2 -3.925,2.275; 3 -3.925,1.625; 4 -3.925,0.975; 5 -3.925,0.325; 6 -3.925,-0.325; 7 -3.925,-0.975; 8 -3.925,-1.625; 9 -3.925,-2.275; 10 -3.925,-2.925; 11 3.925,-2.925; 12 3.925,-2.275; 13 3.925,-1.625; 14 3.925,-0.975; 15 3.925,-0.325; 16 3.925,0.325; 17 3.925,0.975; 18 3.925,1.625; 19 3.925,2.275; 20 3.925,2.925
